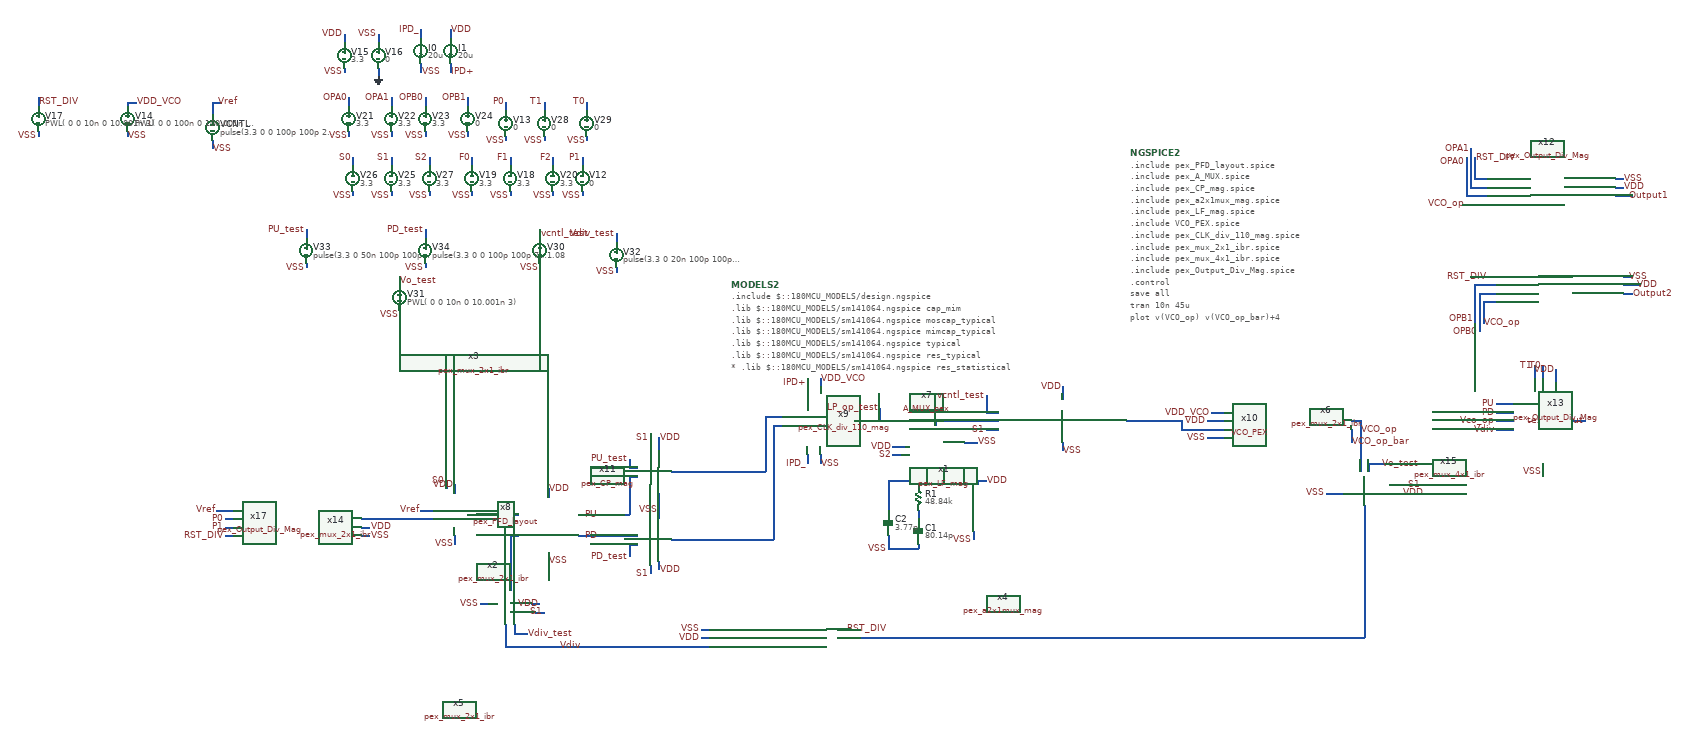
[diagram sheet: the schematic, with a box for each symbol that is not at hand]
v {xschem version=3.1.0 file_version=1.2
}
G {}
K {}
V {}
S {}
E {}
N 290 -470 290 -450 {
lab=VDD}
N 290 -320 290 -300 {
lab=VSS}
N 200 -410 220 -410 {
lab=#net1}
N 200 -360 220 -360 {
lab=#net2}
N 360 -360 380 -360 {
lab=PD}
N 180 -410 200 -410 {
lab=#net1}
N 380 -410 470 -410 {
lab=PU}
N 380 -360 470 -360 {
lab=PD}
N 200 -360 200 -230 {
lab=#net2}
N 210 -100 500 -100 {
lab=Vdiv}
N 200 -100 210 -100 {
lab=Vdiv}
N 360 -410 380 -410 {
lab=PU}
N 500 -100 670 -100 {
lab=Vdiv}
N 1000 -120 1650 -120 {
lab=#net3}
N 2200 -610 2200 -590 {
lab=VCO_op}
N 970 -120 990 -120 {
lab=#net3}
N 990 -120 1000 -120 {
lab=#net3}
N 930 -730 930 -710 {
lab=VDD_VCO}
N 930 -550 930 -530 {
lab=VSS}
N 820 -640 840 -640 {
lab=#net4}
N 900 -730 900 -710 {
lab=IPD+}
N 900 -550 900 -530 {
lab=IPD_}
N 2200 -630 2200 -610 {
lab=VCO_op}
N 2180 -630 2200 -630 {
lab=VCO_op}
N 2180 -610 2180 -580 {
lab=VCO_op_bar}
N 660 -120 670 -120 {
lab=VDD}
N 650 -120 660 -120 {
lab=VDD}
N 650 -140 670 -140 {
lab=VSS}
N 970 -140 1000 -140 {
lab=RST_DIV}
N 1850 -650 1880 -650 {
lab=VDD_VCO}
N 1290 -370 1290 -350 {
lab=VSS}
N 1300 -490 1300 -480 {
lab=VDD}
N 1300 -490 1320 -490 {
lab=VDD}
N 1100 -550 1120 -550 {
lab=S2}
N 1100 -570 1120 -570 {
lab=VDD}
N 1270 -580 1300 -580 {
lab=VSS}
N 1090 -360 1090 -330 {
lab=VSS}
N 1090 -330 1160 -330 {
lab=VSS}
N 1090 -490 1090 -420 {
lab=#net5}
N 1090 -490 1160 -490 {
lab=#net5}
N 1160 -490 1160 -480 {
lab=#net5}
N 1120 -570 1130 -570 {
lab=VDD}
N 1080 -630 1260 -630 {
lab=LP_op_test}
N 1160 -420 1160 -400 {
lab=#net6}
N 1160 -340 1160 -330 {
lab=VSS}
N 1160 -490 1180 -490 {
lab=#net5}
N 1180 -520 1180 -490 {
lab=#net5}
N 1270 -490 1270 -480 {
lab=#net7}
N 1220 -490 1270 -490 {
lab=#net7}
N 1220 -520 1220 -490 {
lab=#net7}
N 1200 -630 1200 -620 {
lab=LP_op_test}
N 1010 -630 1080 -630 {
lab=LP_op_test}
N 550 -460 550 -400 {
lab=VSS}
N 480 -500 500 -500 {
lab=PU}
N 480 -500 480 -410 {
lab=PU}
N 470 -410 480 -410 {
lab=PU}
N 530 -600 530 -570 {
lab=S1}
N 480 -520 500 -520 {
lab=PU_test}
N 480 -540 480 -520 {
lab=PU_test}
N 480 -340 500 -340 {
lab=PD_test}
N 480 -340 480 -310 {
lab=PD_test}
N 470 -360 500 -360 {
lab=PD}
N 580 -350 650 -350 {
lab=#net8}
N 830 -620 840 -620 {
lab=#net8}
N 580 -510 630 -510 {
lab=#net4}
N 810 -640 820 -640 {
lab=#net4}
N 550 -590 550 -560 {
lab=VDD}
N 550 -300 550 -280 {
lab=VDD}
N 530 -290 530 -270 {
lab=S1}
N 650 -350 820 -350 {
lab=#net8}
N 820 -620 820 -350 {
lab=#net8}
N 820 -620 830 -620 {
lab=#net8}
N 800 -640 810 -640 {
lab=#net4}
N 800 -640 800 -510 {
lab=#net4}
N 630 -510 800 -510 {
lab=#net4}
N 1650 -120 1940 -120 {
lab=#net3}
N 210 -150 210 -130 {
lab=Vdiv_test}
N 210 -130 240 -130 {
lab=Vdiv_test}
N 190 -150 190 -120 {
lab=Vdiv}
N 250 -200 270 -200 {
lab=VDD}
N 260 -180 280 -180 {
lab=S1}
N 190 -100 200 -100 {
lab=Vdiv}
N 190 -120 190 -100 {
lab=Vdiv}
N 130 -200 150 -200 {
lab=VSS}
N 2200 -590 2200 -510 {
lab=VCO_op}
N 2270 -480 2310 -480 {
lab=S1}
N 2220 -530 2220 -510 {
lab=Vo_test}
N 2220 -530 2260 -530 {
lab=Vo_test}
N 2260 -460 2300 -460 {
lab=VDD}
N 2120 -460 2160 -460 {
lab=VSS}
N 1260 -630 1350 -630 {
lab=LP_op_test}
N 1320 -650 1350 -650 {
lab=vcntl_test}
N 1320 -690 1320 -650 {
lab=vcntl_test}
N 1320 -610 1350 -610 {
lab=S1}
N 1650 -630 1780 -630 {
lab=#net9}
N 1500 -710 1500 -680 {
lab=VDD}
N 1500 -580 1500 -560 {
lab=VSS}
N 1940 -120 2200 -120 {
lab=#net3}
N 1780 -630 1780 -610 {
lab=#net9}
N 1780 -610 1880 -610 {
lab=#net9}
N 1840 -590 1880 -590 {
lab=VSS}
N 1840 -630 1880 -630 {
lab=VDD}
N 2210 -430 2210 -250 {
lab=#net3}
N 2210 -250 2210 -120 {
lab=#net3}
N 2200 -120 2210 -120 {
lab=#net3}
N 1070 -660 1070 -630 {
lab=LP_op_test}
N 2470 -1200 2500 -1200 {
lab=RST_DIV}
N 2470 -1250 2470 -1200 {
lab=RST_DIV}
N 2440 -1140 2500 -1140 {
lab=VCO_op}
N 2460 -1180 2500 -1180 {
lab=OPA1}
N 2460 -1250 2460 -1180 {
lab=OPA1}
N 2450 -1160 2500 -1160 {
lab=OPA0}
N 2450 -1250 2450 -1160 {
lab=OPA0}
N 2800 -1200 2820 -1200 {
lab=VSS}
N 2800 -1180 2820 -1180 {
lab=VDD}
N 2800 -1160 2840 -1160 {
lab=Output1}
N 2460 -1270 2460 -1250 {
lab=OPA1}
N 2490 -910 2520 -910 {
lab=VCO_op}
N 2490 -910 2490 -860 {
lab=VCO_op}
N 2460 -970 2520 -970 {
lab=RST_DIV}
N 2480 -930 2520 -930 {
lab=OPB0}
N 2480 -930 2480 -860 {
lab=OPB0}
N 2470 -950 2520 -950 {
lab=OPB1}
N 2470 -950 2470 -860 {
lab=OPB1}
N 2820 -970 2840 -970 {
lab=VSS}
N 2820 -930 2840 -930 {
lab=Output2}
N 2820 -950 2860 -950 {
lab=VDD}
N 2480 -860 2480 -840 {
lab=OPB0}
N 2520 -670 2560 -670 {
lab=PU}
N 2520 -650 2560 -650 {
lab=PD}
N 2520 -630 2560 -630 {
lab=Vco_op}
N 2520 -610 2560 -610 {
lab=Vdiv}
N 2660 -750 2660 -720 {
lab=VDD}
N 2630 -760 2630 -730 {
lab=T0}
N 2610 -760 2610 -730 {
lab=T1}
N 2630 -530 2630 -510 {
lab=VSS}
N 2700 -630 2730 -630 {
lab=test_output}
N -470 -400 -450 -400 {
lab=P0}
N -470 -380 -450 -380 {
lab=P1}
N -470 -360 -450 -360 {
lab=RST_DIV}
N -150 -360 -130 -360 {
lab=VSS}
N -150 -380 -130 -380 {
lab=VDD}
N -60 -400 -30 -400 {
lab=#net10}
N -490 -420 -460 -420 {
lab=Vref}
N -150 -400 -80 -400 {
lab=#net10}
N -80 -400 -60 -400 {
lab=#net10}
N -460 -420 -450 -420 {
lab=Vref}
N 70 -360 70 -340 {
lab=VSS}
N 70 -480 70 -460 {
lab=VDD}
N 50 -490 50 -470 {
lab=S0}
N -30 -400 20 -400 {
lab=#net10}
N -10 -420 20 -420 {
lab=Vref}
N 100 -410 180 -410 {
lab=#net1}
N 370 -1170 370 -1160 {
lab=VSS}
N 370 -1250 370 -1230 {
lab=P1}
N 190 -1300 190 -1290 {
lab=VSS}
N 190 -1380 190 -1360 {
lab=P0}
N -500 -1290 -500 -1270 {
lab=VSS}
N -700 -1310 -700 -1300 {
lab=VSS}
N -500 -1380 -480 -1380 {
lab=Vref}
N -190 -1460 -190 -1450 {
lab=VSS}
N -190 -1540 -190 -1520 {
lab=VDD}
N -110 -1540 -110 -1520 {
lab=VSS}
N -110 -1460 -110 -1440 {
lab=GND}
N -910 -1310 -910 -1300 {
lab=VSS}
N -910 -1390 -910 -1370 {
lab=RST_DIV}
N -700 -1380 -700 -1370 {
lab=VDD_VCO}
N -700 -1380 -680 -1380 {
lab=VDD_VCO}
N 200 -1170 200 -1160 {
lab=VSS}
N 200 -1250 200 -1230 {
lab=F1}
N 110 -1170 110 -1160 {
lab=VSS}
N 110 -1250 110 -1230 {
lab=F0}
N 300 -1170 300 -1160 {
lab=VSS}
N 300 -1250 300 -1230 {
lab=F2}
N -180 -1310 -180 -1300 {
lab=VSS}
N -180 -1390 -180 -1370 {
lab=OPA0}
N -80 -1310 -80 -1300 {
lab=VSS}
N -80 -1390 -80 -1370 {
lab=OPA1}
N 0 -1310 0 -1300 {
lab=VSS}
N 0 -1390 0 -1370 {
lab=OPB0}
N 100 -1310 100 -1300 {
lab=VSS}
N 100 -1390 100 -1370 {
lab=OPB1}
N -10 -1470 -10 -1450 {
lab=VSS}
N 60 -1470 60 -1450 {
lab=IPD+}
N -10 -1550 -10 -1530 {
lab=IPD_}
N 60 -1550 60 -1530 {
lab=VDD}
N -80 -1170 -80 -1160 {
lab=VSS}
N -80 -1250 -80 -1230 {
lab=S1}
N -500 -1380 -500 -1350 {
lab=Vref}
N -170 -1170 -170 -1160 {
lab=VSS}
N -170 -1250 -170 -1230 {
lab=S0}
N 10 -1170 10 -1160 {
lab=VSS}
N 10 -1250 10 -1230 {
lab=S2}
N 280 -1300 280 -1290 {
lab=VSS}
N 280 -1380 280 -1360 {
lab=T1}
N 380 -1300 380 -1290 {
lab=VSS}
N 380 -1380 380 -1360 {
lab=T0}
N 270 -1000 270 -990 {
lab=VSS}
N 270 -1080 270 -1060 {
lab=vcntl_test}
N -60 -890 -60 -880 {
lab=VSS}
N -60 -970 -60 -950 {
lab=Vo_test}
N 450 -990 450 -980 {
lab=VSS}
N 450 -1070 450 -1050 {
lab=Vdiv_test}
N -280 -1000 -280 -990 {
lab=VSS}
N -280 -1080 -280 -1060 {
lab=PU_test}
N 0 -1000 0 -990 {
lab=VSS}
N 0 -1080 0 -1060 {
lab=PD_test}
C {devices/lab_pin.sym} 290 -470 2 0 {name=p22 sig_type=std_logic lab=VDD}
C {devices/lab_wire.sym} 290 -300 2 0 {name=p23 sig_type=std_logic lab=VSS}
C {devices/lab_pin.sym} 370 -100 3 0 {name=p25 sig_type=std_logic lab=Vdiv
}
C {devices/lab_pin.sym} 2200 -610 2 0 {name=p26 sig_type=std_logic lab=VCO_op
}
C {devices/code_shown.sym} 1660 -1260 0 1 {name=NGSPICE2 only_toplevel=true
value="
.include "pex_PFD_layout.spice"
.include "pex_A_MUX.spice"
.include "pex_CP_mag.spice"
.include "pex_a2x1mux_mag.spice"
.include "pex_LF_mag.spice"
.include "VCO_PEX.spice"
.include "pex_CLK_div_110_mag.spice"
.include "pex_mux_2x1_ibr.spice"
.include "pex_mux_4x1_ibr.spice"
.include "pex_Output_Div_Mag.spice"
.control
save all
tran 10n 45u 
plot v(VCO_op) v(VCO_op_bar)+4
plot v(vcntl)
plot v(Vdiv)
plot v(vref)
**write pll_4.raw
.endc
"}
C {devices/lab_pin.sym} 2180 -580 2 0 {name=p31 sig_type=std_logic lab=VCO_op_bar
}
C {devices/lab_pin.sym} 410 -410 1 0 {name=p37 sig_type=std_logic lab=PU}
C {devices/lab_pin.sym} 410 -360 1 0 {name=p40 sig_type=std_logic lab=PD}
C {devices/lab_wire.sym} 930 -530 2 0 {name=p68 sig_type=std_logic lab=VSS}
C {devices/lab_wire.sym} 900 -720 0 0 {name=p70 sig_type=std_logic lab=IPD+}
C {devices/lab_wire.sym} 900 -530 0 0 {name=p71 sig_type=std_logic lab=IPD_}
C {devices/code_shown.sym} 720 -950 0 0 {name=MODELS2 only_toplevel=true
format="tcleval( @value )"
value="
.include $::180MCU_MODELS/design.ngspice
.lib $::180MCU_MODELS/sm141064.ngspice cap_mim
.lib $::180MCU_MODELS/sm141064.ngspice moscap_typical
.lib $::180MCU_MODELS/sm141064.ngspice mimcap_typical
.lib $::180MCU_MODELS/sm141064.ngspice typical
.lib $::180MCU_MODELS/sm141064.ngspice res_typical
* .lib $::180MCU_MODELS/sm141064.ngspice res_statistical
"}
C {devices/lab_wire.sym} 650 -140 0 0 {name=p78 sig_type=std_logic lab=VSS}
C {devices/lab_pin.sym} 650 -120 0 0 {name=p79 sig_type=std_logic lab=VDD}
C {devices/lab_pin.sym} 990 -140 2 0 {name=p80 sig_type=std_logic lab=RST_DIV}
C {pex_CLK_div_110_mag.sym} 820 -120 0 1 {name=x9}
C {pex_CP_mag.sym} 350 -430 0 0 {name=x11}
C {devices/lab_pin.sym} 930 -730 2 0 {name=p81 sig_type=std_logic lab=VDD_VCO}
C {devices/lab_pin.sym} 1850 -650 0 0 {name=p89 sig_type=std_logic lab=VDD_VCO}
C {devices/lab_wire.sym} 1290 -350 2 1 {name=p5 sig_type=std_logic lab=VSS}
C {devices/lab_wire.sym} 1320 -490 0 1 {name=p21 sig_type=std_logic lab=VDD}
C {devices/lab_wire.sym} 1300 -580 2 0 {name=p6 sig_type=std_logic lab=VSS}
C {devices/lab_wire.sym} 1100 -570 2 1 {name=p1 sig_type=std_logic lab=VDD}
C {devices/lab_wire.sym} 1100 -550 1 1 {name=p2 sig_type=std_logic lab=S2}
C {devices/capa.sym} 1160 -370 0 0 {name=C1
m=1
value=80.14p
footprint=1206
device="ceramic capacitor"}
C {devices/capa.sym} 1090 -390 0 0 {name=C2
m=1
value=3.77p
footprint=1206
device="ceramic capacitor"}
C {devices/res.sym} 1160 -450 0 0 {name=R1
value=48.84k
footprint=1206
device=resistor
m=1}
C {devices/lab_wire.sym} 1090 -330 2 1 {name=p3 sig_type=std_logic lab=VSS}
C {pex_a2x1mux_mag.sym} 1360 -200 3 0 {name=x4}
C {pex_LF_mag.sym} 1430 -320 0 1 {name=x1}
C {pex_mux_2x1_ibr.sym} 300 -390 0 0 {name=x2}
C {pex_mux_2x1_ibr.sym} 300 -470 2 1 {name=x3}
C {devices/lab_wire.sym} 550 -420 0 0 {name=p4 sig_type=std_logic lab=VSS
}
C {devices/lab_wire.sym} 550 -590 2 0 {name=p7 sig_type=std_logic lab=VDD}
C {devices/lab_wire.sym} 550 -280 2 0 {name=p8 sig_type=std_logic lab=VDD}
C {devices/lab_wire.sym} 530 -590 0 0 {name=p10 sig_type=std_logic lab=S1}
C {devices/lab_wire.sym} 530 -270 0 0 {name=p9 sig_type=std_logic lab=S1}
C {devices/lab_pin.sym} 480 -540 0 0 {name=p11 sig_type=std_logic lab=PU_test}
C {devices/lab_pin.sym} 480 -310 0 0 {name=p12 sig_type=std_logic lab=PD_test}
C {pex_mux_2x1_ibr.sym} 80 50 1 1 {name=x5}
C {devices/lab_wire.sym} 130 -200 3 0 {name=p13 sig_type=std_logic lab=VSS
}
C {devices/lab_wire.sym} 270 -200 1 0 {name=p14 sig_type=std_logic lab=VDD}
C {devices/lab_wire.sym} 280 -180 3 0 {name=p15 sig_type=std_logic lab=S1}
C {devices/lab_pin.sym} 240 -130 2 0 {name=p16 sig_type=std_logic lab=Vdiv_test}
C {devices/lab_wire.sym} 2310 -480 0 1 {name=p36 sig_type=std_logic lab=S1}
C {devices/lab_wire.sym} 2300 -460 0 1 {name=p38 sig_type=std_logic lab=VDD}
C {devices/lab_wire.sym} 2120 -460 0 0 {name=p39 sig_type=std_logic lab=VSS}
C {devices/lab_pin.sym} 2250 -530 2 0 {name=p47 sig_type=std_logic lab=Vo_test
}
C {A_MUX_pex.sym} 1500 -630 0 0 {name=x7}
C {devices/lab_wire.sym} 1320 -610 2 1 {name=p48 sig_type=std_logic lab=S1}
C {devices/lab_wire.sym} 1320 -690 1 0 {name=p49 sig_type=std_logic lab=vcntl_test}
C {devices/lab_wire.sym} 1500 -710 2 1 {name=p50 sig_type=std_logic lab=VDD}
C {devices/lab_wire.sym} 1500 -560 2 0 {name=p51 sig_type=std_logic lab=VSS}
C {devices/lab_wire.sym} 1840 -590 3 0 {name=p52 sig_type=std_logic lab=VSS}
C {devices/lab_wire.sym} 1840 -630 2 1 {name=p53 sig_type=std_logic lab=VDD}
C {pex_mux_2x1_ibr.sym} 2090 -710 1 0 {name=x6}
C {devices/lab_wire.sym} 1070 -660 1 0 {name=p20 sig_type=std_logic lab=LP_op_test}
C {pex_PFD_layout.sym} 0 -200 0 0 {name=x8}
C {VCO_PEX.sym} 2030 -620 0 0 {name=x10}
C {devices/lab_pin.sym} 2820 -1180 2 0 {name=p56 sig_type=std_logic lab=VDD}
C {devices/lab_pin.sym} 2820 -1200 2 0 {name=p57 sig_type=std_logic lab=VSS}
C {devices/lab_wire.sym} 2450 -1240 0 0 {name=p82 sig_type=std_logic lab=OPA0}
C {devices/lab_wire.sym} 2460 -1270 0 0 {name=p83 sig_type=std_logic lab=OPA1}
C {devices/lab_pin.sym} 2470 -1250 2 0 {name=p58 sig_type=std_logic lab=RST_DIV}
C {devices/lab_pin.sym} 2830 -1160 2 0 {name=p84 sig_type=std_logic lab=Output1}
C {devices/lab_pin.sym} 2850 -950 0 1 {name=p85 sig_type=std_logic lab=VDD}
C {devices/lab_pin.sym} 2830 -970 0 1 {name=p86 sig_type=std_logic lab=VSS}
C {devices/lab_wire.sym} 2470 -870 2 1 {name=p87 sig_type=std_logic lab=OPB1}
C {devices/lab_wire.sym} 2480 -840 2 1 {name=p88 sig_type=std_logic lab=OPB0}
C {devices/lab_pin.sym} 2840 -930 0 1 {name=p90 sig_type=std_logic lab=Output2}
C {devices/lab_pin.sym} 2500 -970 1 0 {name=p59 sig_type=std_logic lab=RST_DIV}
C {devices/lab_pin.sym} 2490 -860 2 0 {name=p60 sig_type=std_logic lab=VCO_op
}
C {devices/lab_pin.sym} 2450 -1140 2 1 {name=p61 sig_type=std_logic lab=VCO_op
}
C {devices/lab_pin.sym} 2520 -670 0 0 {name=p97 sig_type=std_logic lab=PU}
C {devices/lab_pin.sym} 2520 -650 0 0 {name=p103 sig_type=std_logic lab=PD}
C {devices/lab_pin.sym} 2520 -630 0 0 {name=p104 sig_type=std_logic lab=Vco_op
}
C {devices/lab_pin.sym} 2520 -610 0 0 {name=p105 sig_type=std_logic lab=Vdiv
}
C {devices/lab_pin.sym} 2610 -760 1 0 {name=p107 sig_type=std_logic lab=T1}
C {devices/lab_pin.sym} 2630 -760 1 0 {name=p108 sig_type=std_logic lab=T0}
C {devices/lab_pin.sym} 2660 -750 3 1 {name=p109 sig_type=std_logic lab=VDD}
C {devices/lab_wire.sym} 2630 -510 3 0 {name=p110 sig_type=std_logic lab=VSS}
C {devices/lab_pin.sym} 2730 -630 1 1 {name=p111 sig_type=std_logic lab=test_output}
C {devices/lab_pin.sym} -470 -380 0 0 {name=p139 sig_type=std_logic lab=P1}
C {devices/lab_pin.sym} -470 -400 0 0 {name=p140 sig_type=std_logic lab=P0}
C {devices/lab_pin.sym} -490 -420 0 0 {name=p141 sig_type=std_logic lab=Vref
}
C {devices/lab_pin.sym} -130 -360 2 0 {name=p142 sig_type=std_logic lab=VSS}
C {devices/lab_pin.sym} -130 -380 2 0 {name=p143 sig_type=std_logic lab=VDD}
C {devices/lab_pin.sym} -470 -360 0 0 {name=p144 sig_type=std_logic lab=RST_DIV}
C {devices/lab_wire.sym} 70 -340 3 0 {name=p62 sig_type=std_logic lab=VSS}
C {devices/lab_pin.sym} 70 -480 3 1 {name=p63 sig_type=std_logic lab=VDD}
C {devices/lab_pin.sym} 50 -490 1 0 {name=p69 sig_type=std_logic lab=S0}
C {devices/lab_pin.sym} -10 -420 1 0 {name=p64 sig_type=std_logic lab=Vref
}
C {pex_mux_2x1_ibr.sym} -180 -290 0 0 {name=x14}
C {pex_Output_Div_Mag.sym} 2650 -1170 0 0 {name=x12}
C {pex_Output_Div_Mag.sym} 2670 -940 0 0 {name=x13}
C {pex_Output_Div_Mag.sym} -300 -390 2 1 {name=x17}
C {devices/vsource.sym} 370 -1200 0 0 {name=V12 value=0}
C {devices/lab_wire.sym} 370 -1160 0 0 {name=p65 sig_type=std_logic lab=VSS
}
C {devices/lab_wire.sym} 370 -1250 0 0 {name=p66 sig_type=std_logic lab=P1}
C {devices/vsource.sym} 190 -1330 0 0 {name=V13 value=0}
C {devices/lab_wire.sym} 190 -1290 0 0 {name=p76 sig_type=std_logic lab=VSS
}
C {devices/lab_wire.sym} 190 -1380 0 0 {name=p77 sig_type=std_logic lab=P0}
C {devices/vsource.sym} -500 -1320 0 0 {name=VCNTL value="pulse(3.3 0 0 100p 100p 250n 500n)"}
C {devices/vsource.sym} -700 -1340 0 0 {name=V14 value=" PWL( 0 0 100n 0 100.001n 3.3)"}
C {devices/vsource.sym} -190 -1490 0 0 {name=V15 value=3.3}
C {devices/vsource.sym} -110 -1490 0 0 {name=V16 value=0}
C {devices/lab_wire.sym} -110 -1540 0 0 {name=p91 sig_type=std_logic lab=VSS}
C {devices/lab_wire.sym} -190 -1450 0 0 {name=p92 sig_type=std_logic lab=VSS
}
C {devices/lab_wire.sym} -190 -1540 0 0 {name=p93 sig_type=std_logic lab=VDD}
C {devices/gnd.sym} -110 -1440 0 0 {name=l3 lab=GND}
C {devices/lab_pin.sym} -680 -1380 2 0 {name=p94 sig_type=std_logic lab=VDD_VCO}
C {devices/lab_pin.sym} -490 -1380 2 0 {name=p95 sig_type=std_logic lab=Vref
}
C {devices/lab_wire.sym} -910 -1300 0 0 {name=p96 sig_type=std_logic lab=VSS
}
C {devices/vsource.sym} -910 -1340 0 0 {name=V17 value=" PWL( 0 0 10n 0 10.001n 3)"}
C {devices/vsource.sym} 200 -1200 0 0 {name=V18 value=3.3}
C {devices/lab_wire.sym} 200 -1160 0 0 {name=p98 sig_type=std_logic lab=VSS
}
C {devices/lab_wire.sym} 200 -1250 0 0 {name=p99 sig_type=std_logic lab=F1}
C {devices/vsource.sym} 110 -1200 0 0 {name=V19 value=3.3}
C {devices/lab_wire.sym} 110 -1160 0 0 {name=p100 sig_type=std_logic lab=VSS
}
C {devices/lab_wire.sym} 110 -1250 0 0 {name=p101 sig_type=std_logic lab=F0}
C {devices/vsource.sym} 300 -1200 0 0 {name=V20 value=3.3}
C {devices/lab_wire.sym} 300 -1160 0 0 {name=p102 sig_type=std_logic lab=VSS
}
C {devices/lab_wire.sym} 300 -1250 0 0 {name=p106 sig_type=std_logic lab=F2}
C {devices/vsource.sym} -180 -1340 0 0 {name=V21 value=3.3}
C {devices/lab_wire.sym} -180 -1300 0 0 {name=p112 sig_type=std_logic lab=VSS
}
C {devices/lab_wire.sym} -180 -1390 0 0 {name=p113 sig_type=std_logic lab=OPA0}
C {devices/vsource.sym} -80 -1340 0 0 {name=V22 value=3.3}
C {devices/lab_wire.sym} -80 -1300 0 0 {name=p114 sig_type=std_logic lab=VSS
}
C {devices/lab_wire.sym} -80 -1390 0 0 {name=p115 sig_type=std_logic lab=OPA1}
C {devices/vsource.sym} 0 -1340 0 0 {name=V23 value=3.3}
C {devices/lab_wire.sym} 0 -1300 0 0 {name=p116 sig_type=std_logic lab=VSS
}
C {devices/lab_wire.sym} 0 -1390 0 0 {name=p117 sig_type=std_logic lab=OPB0
}
C {devices/vsource.sym} 100 -1340 0 0 {name=V24 value=0}
C {devices/lab_wire.sym} 100 -1300 0 0 {name=p118 sig_type=std_logic lab=VSS
}
C {devices/lab_wire.sym} 100 -1390 0 0 {name=p119 sig_type=std_logic lab=OPB1}
C {devices/lab_pin.sym} -910 -1380 2 0 {name=p120 sig_type=std_logic lab=RST_DIV}
C {devices/isource.sym} -10 -1500 0 0 {name=I0 value=20u}
C {devices/isource.sym} 60 -1500 0 0 {name=I1 value=20u}
C {devices/lab_wire.sym} -10 -1550 0 0 {name=p121 sig_type=std_logic lab=IPD_}
C {devices/lab_wire.sym} 60 -1450 2 0 {name=p122 sig_type=std_logic lab=IPD+}
C {devices/lab_wire.sym} -10 -1450 2 0 {name=p123 sig_type=std_logic lab=VSS}
C {devices/lab_wire.sym} 60 -1550 2 0 {name=p124 sig_type=std_logic lab=VDD}
C {devices/lab_wire.sym} -700 -1300 2 0 {name=p125 sig_type=std_logic lab=VSS
}
C {devices/lab_wire.sym} -500 -1270 2 0 {name=p126 sig_type=std_logic lab=VSS
}
C {devices/vsource.sym} -80 -1200 0 0 {name=V25 value=3.3}
C {devices/lab_wire.sym} -80 -1160 0 0 {name=p127 sig_type=std_logic lab=VSS
}
C {devices/lab_wire.sym} -80 -1250 0 0 {name=p128 sig_type=std_logic lab=S1}
C {devices/vsource.sym} -170 -1200 0 0 {name=V26 value=3.3}
C {devices/lab_wire.sym} -170 -1160 0 0 {name=p129 sig_type=std_logic lab=VSS
}
C {devices/lab_wire.sym} -170 -1250 0 0 {name=p130 sig_type=std_logic lab=S0}
C {devices/vsource.sym} 10 -1200 0 0 {name=V27 value=3.3}
C {devices/lab_wire.sym} 10 -1160 0 0 {name=p131 sig_type=std_logic lab=VSS
}
C {devices/lab_wire.sym} 10 -1250 0 0 {name=p132 sig_type=std_logic lab=S2}
C {devices/vsource.sym} 280 -1330 0 0 {name=V28 value=0}
C {devices/lab_wire.sym} 280 -1290 0 0 {name=p133 sig_type=std_logic lab=VSS
}
C {devices/lab_wire.sym} 280 -1380 0 0 {name=p134 sig_type=std_logic lab=T1}
C {devices/vsource.sym} 380 -1330 0 0 {name=V29 value=0}
C {devices/lab_wire.sym} 380 -1290 0 0 {name=p135 sig_type=std_logic lab=VSS
}
C {devices/lab_wire.sym} 380 -1380 0 0 {name=p136 sig_type=std_logic lab=T0}
C {devices/lab_wire.sym} 270 -990 0 0 {name=p137 sig_type=std_logic lab=VSS
}
C {devices/vsource.sym} 270 -1030 0 0 {name=V30 value=1.08}
C {devices/lab_pin.sym} 270 -1070 2 0 {name=p138 sig_type=std_logic lab=vcntl_test}
C {devices/lab_wire.sym} -60 -880 0 0 {name=p145 sig_type=std_logic lab=VSS
}
C {devices/vsource.sym} -60 -920 0 0 {name=V31 value=" PWL( 0 0 10n 0 10.001n 3)"}
C {devices/lab_pin.sym} -60 -960 2 0 {name=p146 sig_type=std_logic lab=Vo_test}
C {devices/vsource.sym} 450 -1020 0 0 {name=V32 value="pulse(3.3 0 20n 100p 100p 50n 100n)"}
C {devices/lab_wire.sym} 450 -1070 0 0 {name=p147 sig_type=std_logic lab=Vdiv_test}
C {devices/lab_wire.sym} 450 -980 0 0 {name=p148 sig_type=std_logic lab=VSS}
C {devices/vsource.sym} -280 -1030 0 0 {name=V33 value="pulse(3.3 0 50n 100p 100p 75n 100n)"}
C {devices/lab_wire.sym} -280 -1080 0 0 {name=p149 sig_type=std_logic lab=PU_test}
C {devices/lab_wire.sym} -280 -990 0 0 {name=p150 sig_type=std_logic lab=VSS}
C {devices/vsource.sym} 0 -1030 0 0 {name=V34 value="pulse(3.3 0 0 100p 100p 75n 100n)"}
C {devices/lab_wire.sym} 0 -1080 0 0 {name=p151 sig_type=std_logic lab=PD_test}
C {devices/lab_wire.sym} 0 -990 0 0 {name=p152 sig_type=std_logic lab=VSS}
C {pex_mux_4x1_ibr.sym} 2280 -520 0 0 {name=x15}
